# OpenTallas memory compiler (tools/mem_compiler), ASAP7 abstract view, track-aligned v2 (build_aligned_v2.py)
VERSION 5.7 ;
BUSBITCHARS "[]" ;
DIVIDERCHAR "/" ;
PROPERTYDEFINITIONS
  MACRO width INTEGER ;
  MACRO depth INTEGER ;
  MACRO banks INTEGER ;
END PROPERTYDEFINITIONS
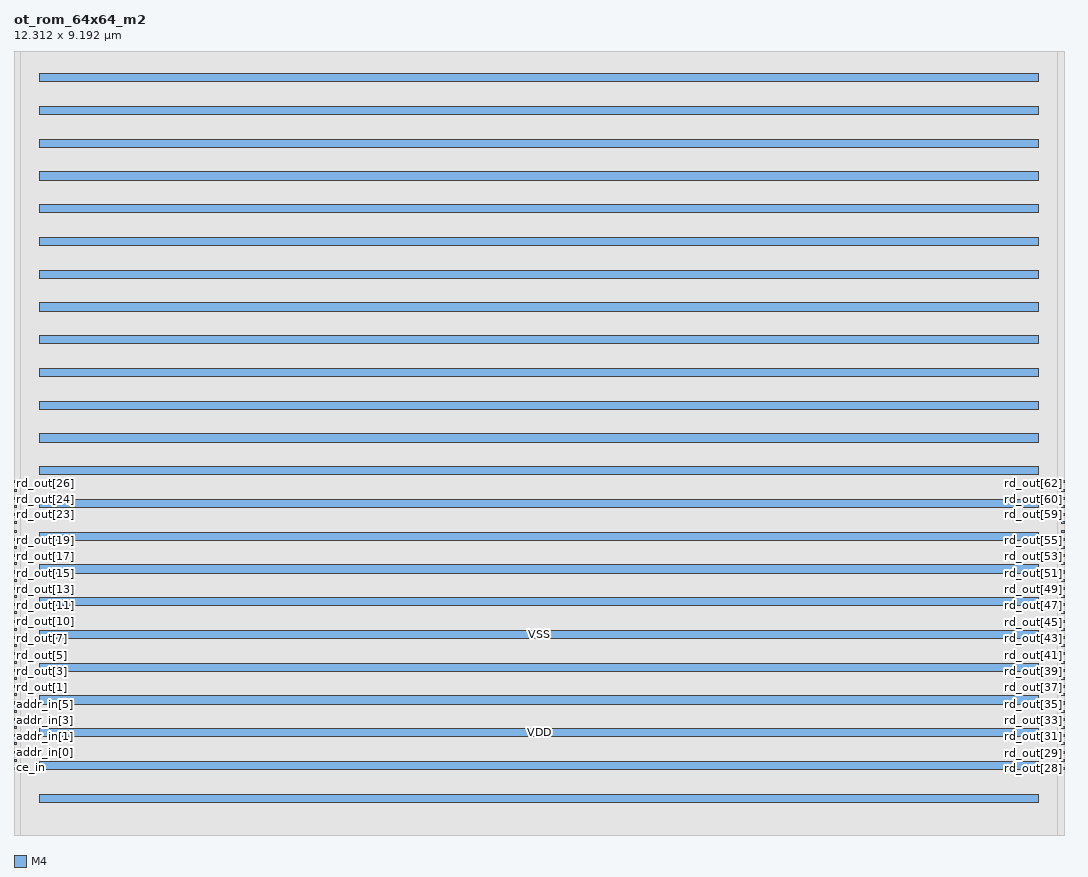
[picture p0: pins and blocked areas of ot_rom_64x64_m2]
MACRO ot_rom_64x64_m2
  PROPERTY width 64 ;
  PROPERTY depth 64 ;
  PROPERTY banks 1 ;
  FOREIGN ot_rom_64x64_m2 0 0 ;
  SYMMETRY X Y ;
  SIZE 12.312 BY 9.192 ;
  CLASS BLOCK ;
  PIN clk
    DIRECTION INPUT ;
    USE CLOCK ;
    SHAPE ABUTMENT ;
    PORT
      LAYER M4 ;
      RECT 0.000 0.768 0.024 0.792 ;
    END
  END clk
  PIN ce_in
    DIRECTION INPUT ;
    USE SIGNAL ;
    SHAPE ABUTMENT ;
    PORT
      LAYER M4 ;
      RECT 0.000 0.864 0.024 0.888 ;
    END
  END ce_in
  PIN addr_in[0]
    DIRECTION INPUT ;
    USE SIGNAL ;
    SHAPE ABUTMENT ;
    PORT
      LAYER M4 ;
      RECT 0.000 0.960 0.024 0.984 ;
    END
  END addr_in[0]
  PIN addr_in[1]
    DIRECTION INPUT ;
    USE SIGNAL ;
    SHAPE ABUTMENT ;
    PORT
      LAYER M4 ;
      RECT 0.000 1.056 0.024 1.080 ;
    END
  END addr_in[1]
  PIN addr_in[2]
    DIRECTION INPUT ;
    USE SIGNAL ;
    SHAPE ABUTMENT ;
    PORT
      LAYER M4 ;
      RECT 0.000 1.152 0.024 1.176 ;
    END
  END addr_in[2]
  PIN addr_in[3]
    DIRECTION INPUT ;
    USE SIGNAL ;
    SHAPE ABUTMENT ;
    PORT
      LAYER M4 ;
      RECT 0.000 1.248 0.024 1.272 ;
    END
  END addr_in[3]
  PIN addr_in[4]
    DIRECTION INPUT ;
    USE SIGNAL ;
    SHAPE ABUTMENT ;
    PORT
      LAYER M4 ;
      RECT 0.000 1.344 0.024 1.368 ;
    END
  END addr_in[4]
  PIN addr_in[5]
    DIRECTION INPUT ;
    USE SIGNAL ;
    SHAPE ABUTMENT ;
    PORT
      LAYER M4 ;
      RECT 0.000 1.440 0.024 1.464 ;
    END
  END addr_in[5]
  PIN rd_out[0]
    DIRECTION OUTPUT ;
    USE SIGNAL ;
    SHAPE ABUTMENT ;
    PORT
      LAYER M4 ;
      RECT 0.000 1.536 0.024 1.560 ;
    END
  END rd_out[0]
  PIN rd_out[1]
    DIRECTION OUTPUT ;
    USE SIGNAL ;
    SHAPE ABUTMENT ;
    PORT
      LAYER M4 ;
      RECT 0.000 1.632 0.024 1.656 ;
    END
  END rd_out[1]
  PIN rd_out[2]
    DIRECTION OUTPUT ;
    USE SIGNAL ;
    SHAPE ABUTMENT ;
    PORT
      LAYER M4 ;
      RECT 0.000 1.728 0.024 1.752 ;
    END
  END rd_out[2]
  PIN rd_out[3]
    DIRECTION OUTPUT ;
    USE SIGNAL ;
    SHAPE ABUTMENT ;
    PORT
      LAYER M4 ;
      RECT 0.000 1.824 0.024 1.848 ;
    END
  END rd_out[3]
  PIN rd_out[4]
    DIRECTION OUTPUT ;
    USE SIGNAL ;
    SHAPE ABUTMENT ;
    PORT
      LAYER M4 ;
      RECT 0.000 1.920 0.024 1.944 ;
    END
  END rd_out[4]
  PIN rd_out[5]
    DIRECTION OUTPUT ;
    USE SIGNAL ;
    SHAPE ABUTMENT ;
    PORT
      LAYER M4 ;
      RECT 0.000 2.016 0.024 2.040 ;
    END
  END rd_out[5]
  PIN rd_out[6]
    DIRECTION OUTPUT ;
    USE SIGNAL ;
    SHAPE ABUTMENT ;
    PORT
      LAYER M4 ;
      RECT 0.000 2.112 0.024 2.136 ;
    END
  END rd_out[6]
  PIN rd_out[7]
    DIRECTION OUTPUT ;
    USE SIGNAL ;
    SHAPE ABUTMENT ;
    PORT
      LAYER M4 ;
      RECT 0.000 2.208 0.024 2.232 ;
    END
  END rd_out[7]
  PIN rd_out[8]
    DIRECTION OUTPUT ;
    USE SIGNAL ;
    SHAPE ABUTMENT ;
    PORT
      LAYER M4 ;
      RECT 0.000 2.304 0.024 2.328 ;
    END
  END rd_out[8]
  PIN rd_out[9]
    DIRECTION OUTPUT ;
    USE SIGNAL ;
    SHAPE ABUTMENT ;
    PORT
      LAYER M4 ;
      RECT 0.000 2.400 0.024 2.424 ;
    END
  END rd_out[9]
  PIN rd_out[10]
    DIRECTION OUTPUT ;
    USE SIGNAL ;
    SHAPE ABUTMENT ;
    PORT
      LAYER M4 ;
      RECT 0.000 2.496 0.024 2.520 ;
    END
  END rd_out[10]
  PIN rd_out[11]
    DIRECTION OUTPUT ;
    USE SIGNAL ;
    SHAPE ABUTMENT ;
    PORT
      LAYER M4 ;
      RECT 0.000 2.592 0.024 2.616 ;
    END
  END rd_out[11]
  PIN rd_out[12]
    DIRECTION OUTPUT ;
    USE SIGNAL ;
    SHAPE ABUTMENT ;
    PORT
      LAYER M4 ;
      RECT 0.000 2.688 0.024 2.712 ;
    END
  END rd_out[12]
  PIN rd_out[13]
    DIRECTION OUTPUT ;
    USE SIGNAL ;
    SHAPE ABUTMENT ;
    PORT
      LAYER M4 ;
      RECT 0.000 2.784 0.024 2.808 ;
    END
  END rd_out[13]
  PIN rd_out[14]
    DIRECTION OUTPUT ;
    USE SIGNAL ;
    SHAPE ABUTMENT ;
    PORT
      LAYER M4 ;
      RECT 0.000 2.880 0.024 2.904 ;
    END
  END rd_out[14]
  PIN rd_out[15]
    DIRECTION OUTPUT ;
    USE SIGNAL ;
    SHAPE ABUTMENT ;
    PORT
      LAYER M4 ;
      RECT 0.000 2.976 0.024 3.000 ;
    END
  END rd_out[15]
  PIN rd_out[16]
    DIRECTION OUTPUT ;
    USE SIGNAL ;
    SHAPE ABUTMENT ;
    PORT
      LAYER M4 ;
      RECT 0.000 3.072 0.024 3.096 ;
    END
  END rd_out[16]
  PIN rd_out[17]
    DIRECTION OUTPUT ;
    USE SIGNAL ;
    SHAPE ABUTMENT ;
    PORT
      LAYER M4 ;
      RECT 0.000 3.168 0.024 3.192 ;
    END
  END rd_out[17]
  PIN rd_out[18]
    DIRECTION OUTPUT ;
    USE SIGNAL ;
    SHAPE ABUTMENT ;
    PORT
      LAYER M4 ;
      RECT 0.000 3.264 0.024 3.288 ;
    END
  END rd_out[18]
  PIN rd_out[19]
    DIRECTION OUTPUT ;
    USE SIGNAL ;
    SHAPE ABUTMENT ;
    PORT
      LAYER M4 ;
      RECT 0.000 3.360 0.024 3.384 ;
    END
  END rd_out[19]
  PIN rd_out[20]
    DIRECTION OUTPUT ;
    USE SIGNAL ;
    SHAPE ABUTMENT ;
    PORT
      LAYER M4 ;
      RECT 0.000 3.456 0.024 3.480 ;
    END
  END rd_out[20]
  PIN rd_out[21]
    DIRECTION OUTPUT ;
    USE SIGNAL ;
    SHAPE ABUTMENT ;
    PORT
      LAYER M4 ;
      RECT 0.000 3.552 0.024 3.576 ;
    END
  END rd_out[21]
  PIN rd_out[22]
    DIRECTION OUTPUT ;
    USE SIGNAL ;
    SHAPE ABUTMENT ;
    PORT
      LAYER M4 ;
      RECT 0.000 3.648 0.024 3.672 ;
    END
  END rd_out[22]
  PIN rd_out[23]
    DIRECTION OUTPUT ;
    USE SIGNAL ;
    SHAPE ABUTMENT ;
    PORT
      LAYER M4 ;
      RECT 0.000 3.744 0.024 3.768 ;
    END
  END rd_out[23]
  PIN rd_out[24]
    DIRECTION OUTPUT ;
    USE SIGNAL ;
    SHAPE ABUTMENT ;
    PORT
      LAYER M4 ;
      RECT 0.000 3.840 0.024 3.864 ;
    END
  END rd_out[24]
  PIN rd_out[25]
    DIRECTION OUTPUT ;
    USE SIGNAL ;
    SHAPE ABUTMENT ;
    PORT
      LAYER M4 ;
      RECT 0.000 3.936 0.024 3.960 ;
    END
  END rd_out[25]
  PIN rd_out[26]
    DIRECTION OUTPUT ;
    USE SIGNAL ;
    SHAPE ABUTMENT ;
    PORT
      LAYER M4 ;
      RECT 0.000 4.032 0.024 4.056 ;
    END
  END rd_out[26]
  PIN rd_out[27]
    DIRECTION OUTPUT ;
    USE SIGNAL ;
    SHAPE ABUTMENT ;
    PORT
      LAYER M4 ;
      RECT 0.000 4.128 0.024 4.152 ;
    END
  END rd_out[27]
  PIN rd_out[28]
    DIRECTION OUTPUT ;
    USE SIGNAL ;
    SHAPE ABUTMENT ;
    PORT
      LAYER M4 ;
      RECT 12.288 0.768 12.312 0.792 ;
    END
  END rd_out[28]
  PIN rd_out[29]
    DIRECTION OUTPUT ;
    USE SIGNAL ;
    SHAPE ABUTMENT ;
    PORT
      LAYER M4 ;
      RECT 12.288 0.864 12.312 0.888 ;
    END
  END rd_out[29]
  PIN rd_out[30]
    DIRECTION OUTPUT ;
    USE SIGNAL ;
    SHAPE ABUTMENT ;
    PORT
      LAYER M4 ;
      RECT 12.288 0.960 12.312 0.984 ;
    END
  END rd_out[30]
  PIN rd_out[31]
    DIRECTION OUTPUT ;
    USE SIGNAL ;
    SHAPE ABUTMENT ;
    PORT
      LAYER M4 ;
      RECT 12.288 1.056 12.312 1.080 ;
    END
  END rd_out[31]
  PIN rd_out[32]
    DIRECTION OUTPUT ;
    USE SIGNAL ;
    SHAPE ABUTMENT ;
    PORT
      LAYER M4 ;
      RECT 12.288 1.152 12.312 1.176 ;
    END
  END rd_out[32]
  PIN rd_out[33]
    DIRECTION OUTPUT ;
    USE SIGNAL ;
    SHAPE ABUTMENT ;
    PORT
      LAYER M4 ;
      RECT 12.288 1.248 12.312 1.272 ;
    END
  END rd_out[33]
  PIN rd_out[34]
    DIRECTION OUTPUT ;
    USE SIGNAL ;
    SHAPE ABUTMENT ;
    PORT
      LAYER M4 ;
      RECT 12.288 1.344 12.312 1.368 ;
    END
  END rd_out[34]
  PIN rd_out[35]
    DIRECTION OUTPUT ;
    USE SIGNAL ;
    SHAPE ABUTMENT ;
    PORT
      LAYER M4 ;
      RECT 12.288 1.440 12.312 1.464 ;
    END
  END rd_out[35]
  PIN rd_out[36]
    DIRECTION OUTPUT ;
    USE SIGNAL ;
    SHAPE ABUTMENT ;
    PORT
      LAYER M4 ;
      RECT 12.288 1.536 12.312 1.560 ;
    END
  END rd_out[36]
  PIN rd_out[37]
    DIRECTION OUTPUT ;
    USE SIGNAL ;
    SHAPE ABUTMENT ;
    PORT
      LAYER M4 ;
      RECT 12.288 1.632 12.312 1.656 ;
    END
  END rd_out[37]
  PIN rd_out[38]
    DIRECTION OUTPUT ;
    USE SIGNAL ;
    SHAPE ABUTMENT ;
    PORT
      LAYER M4 ;
      RECT 12.288 1.728 12.312 1.752 ;
    END
  END rd_out[38]
  PIN rd_out[39]
    DIRECTION OUTPUT ;
    USE SIGNAL ;
    SHAPE ABUTMENT ;
    PORT
      LAYER M4 ;
      RECT 12.288 1.824 12.312 1.848 ;
    END
  END rd_out[39]
  PIN rd_out[40]
    DIRECTION OUTPUT ;
    USE SIGNAL ;
    SHAPE ABUTMENT ;
    PORT
      LAYER M4 ;
      RECT 12.288 1.920 12.312 1.944 ;
    END
  END rd_out[40]
  PIN rd_out[41]
    DIRECTION OUTPUT ;
    USE SIGNAL ;
    SHAPE ABUTMENT ;
    PORT
      LAYER M4 ;
      RECT 12.288 2.016 12.312 2.040 ;
    END
  END rd_out[41]
  PIN rd_out[42]
    DIRECTION OUTPUT ;
    USE SIGNAL ;
    SHAPE ABUTMENT ;
    PORT
      LAYER M4 ;
      RECT 12.288 2.112 12.312 2.136 ;
    END
  END rd_out[42]
  PIN rd_out[43]
    DIRECTION OUTPUT ;
    USE SIGNAL ;
    SHAPE ABUTMENT ;
    PORT
      LAYER M4 ;
      RECT 12.288 2.208 12.312 2.232 ;
    END
  END rd_out[43]
  PIN rd_out[44]
    DIRECTION OUTPUT ;
    USE SIGNAL ;
    SHAPE ABUTMENT ;
    PORT
      LAYER M4 ;
      RECT 12.288 2.304 12.312 2.328 ;
    END
  END rd_out[44]
  PIN rd_out[45]
    DIRECTION OUTPUT ;
    USE SIGNAL ;
    SHAPE ABUTMENT ;
    PORT
      LAYER M4 ;
      RECT 12.288 2.400 12.312 2.424 ;
    END
  END rd_out[45]
  PIN rd_out[46]
    DIRECTION OUTPUT ;
    USE SIGNAL ;
    SHAPE ABUTMENT ;
    PORT
      LAYER M4 ;
      RECT 12.288 2.496 12.312 2.520 ;
    END
  END rd_out[46]
  PIN rd_out[47]
    DIRECTION OUTPUT ;
    USE SIGNAL ;
    SHAPE ABUTMENT ;
    PORT
      LAYER M4 ;
      RECT 12.288 2.592 12.312 2.616 ;
    END
  END rd_out[47]
  PIN rd_out[48]
    DIRECTION OUTPUT ;
    USE SIGNAL ;
    SHAPE ABUTMENT ;
    PORT
      LAYER M4 ;
      RECT 12.288 2.688 12.312 2.712 ;
    END
  END rd_out[48]
  PIN rd_out[49]
    DIRECTION OUTPUT ;
    USE SIGNAL ;
    SHAPE ABUTMENT ;
    PORT
      LAYER M4 ;
      RECT 12.288 2.784 12.312 2.808 ;
    END
  END rd_out[49]
  PIN rd_out[50]
    DIRECTION OUTPUT ;
    USE SIGNAL ;
    SHAPE ABUTMENT ;
    PORT
      LAYER M4 ;
      RECT 12.288 2.880 12.312 2.904 ;
    END
  END rd_out[50]
  PIN rd_out[51]
    DIRECTION OUTPUT ;
    USE SIGNAL ;
    SHAPE ABUTMENT ;
    PORT
      LAYER M4 ;
      RECT 12.288 2.976 12.312 3.000 ;
    END
  END rd_out[51]
  PIN rd_out[52]
    DIRECTION OUTPUT ;
    USE SIGNAL ;
    SHAPE ABUTMENT ;
    PORT
      LAYER M4 ;
      RECT 12.288 3.072 12.312 3.096 ;
    END
  END rd_out[52]
  PIN rd_out[53]
    DIRECTION OUTPUT ;
    USE SIGNAL ;
    SHAPE ABUTMENT ;
    PORT
      LAYER M4 ;
      RECT 12.288 3.168 12.312 3.192 ;
    END
  END rd_out[53]
  PIN rd_out[54]
    DIRECTION OUTPUT ;
    USE SIGNAL ;
    SHAPE ABUTMENT ;
    PORT
      LAYER M4 ;
      RECT 12.288 3.264 12.312 3.288 ;
    END
  END rd_out[54]
  PIN rd_out[55]
    DIRECTION OUTPUT ;
    USE SIGNAL ;
    SHAPE ABUTMENT ;
    PORT
      LAYER M4 ;
      RECT 12.288 3.360 12.312 3.384 ;
    END
  END rd_out[55]
  PIN rd_out[56]
    DIRECTION OUTPUT ;
    USE SIGNAL ;
    SHAPE ABUTMENT ;
    PORT
      LAYER M4 ;
      RECT 12.288 3.456 12.312 3.480 ;
    END
  END rd_out[56]
  PIN rd_out[57]
    DIRECTION OUTPUT ;
    USE SIGNAL ;
    SHAPE ABUTMENT ;
    PORT
      LAYER M4 ;
      RECT 12.288 3.552 12.312 3.576 ;
    END
  END rd_out[57]
  PIN rd_out[58]
    DIRECTION OUTPUT ;
    USE SIGNAL ;
    SHAPE ABUTMENT ;
    PORT
      LAYER M4 ;
      RECT 12.288 3.648 12.312 3.672 ;
    END
  END rd_out[58]
  PIN rd_out[59]
    DIRECTION OUTPUT ;
    USE SIGNAL ;
    SHAPE ABUTMENT ;
    PORT
      LAYER M4 ;
      RECT 12.288 3.744 12.312 3.768 ;
    END
  END rd_out[59]
  PIN rd_out[60]
    DIRECTION OUTPUT ;
    USE SIGNAL ;
    SHAPE ABUTMENT ;
    PORT
      LAYER M4 ;
      RECT 12.288 3.840 12.312 3.864 ;
    END
  END rd_out[60]
  PIN rd_out[61]
    DIRECTION OUTPUT ;
    USE SIGNAL ;
    SHAPE ABUTMENT ;
    PORT
      LAYER M4 ;
      RECT 12.288 3.936 12.312 3.960 ;
    END
  END rd_out[61]
  PIN rd_out[62]
    DIRECTION OUTPUT ;
    USE SIGNAL ;
    SHAPE ABUTMENT ;
    PORT
      LAYER M4 ;
      RECT 12.288 4.032 12.312 4.056 ;
    END
  END rd_out[62]
  PIN rd_out[63]
    DIRECTION OUTPUT ;
    USE SIGNAL ;
    SHAPE ABUTMENT ;
    PORT
      LAYER M4 ;
      RECT 12.288 4.128 12.312 4.152 ;
    END
  END rd_out[63]
  PIN VDD
    DIRECTION INOUT ;
    USE POWER ;
    PORT
      LAYER M4 ;
      RECT 0.300 0.384 12.012 0.480 ;
      RECT 0.300 1.152 12.012 1.248 ;
      RECT 0.300 1.920 12.012 2.016 ;
      RECT 0.300 2.688 12.012 2.784 ;
      RECT 0.300 3.456 12.012 3.552 ;
      RECT 0.300 4.224 12.012 4.320 ;
      RECT 0.300 4.992 12.012 5.088 ;
      RECT 0.300 5.760 12.012 5.856 ;
      RECT 0.300 6.528 12.012 6.624 ;
      RECT 0.300 7.296 12.012 7.392 ;
      RECT 0.300 8.064 12.012 8.160 ;
      RECT 0.300 8.832 12.012 8.928 ;
    END
  END VDD
  PIN VSS
    DIRECTION INOUT ;
    USE GROUND ;
    PORT
      LAYER M4 ;
      RECT 0.300 0.768 12.012 0.864 ;
      RECT 0.300 1.536 12.012 1.632 ;
      RECT 0.300 2.304 12.012 2.400 ;
      RECT 0.300 3.072 12.012 3.168 ;
      RECT 0.300 3.840 12.012 3.936 ;
      RECT 0.300 4.608 12.012 4.704 ;
      RECT 0.300 5.376 12.012 5.472 ;
      RECT 0.300 6.144 12.012 6.240 ;
      RECT 0.300 6.912 12.012 7.008 ;
      RECT 0.300 7.680 12.012 7.776 ;
      RECT 0.300 8.448 12.012 8.544 ;
    END
  END VSS
  OBS
    LAYER M1 ;
    RECT 0 0 12.312 9.192 ;
    LAYER M2 ;
    RECT 0 0 12.312 9.192 ;
    LAYER M3 ;
    RECT 0 0 12.312 9.192 ;
    LAYER M4 ;
    RECT 0.072 0 12.240 9.192 ;
  END
END ot_rom_64x64_m2

END LIBRARY
